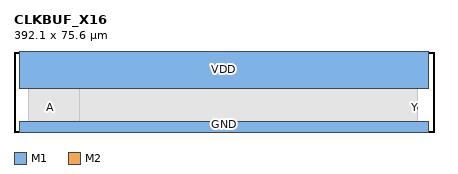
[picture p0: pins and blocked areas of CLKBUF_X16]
MACRO CLKBUF_X16
  CLASS CORE ;
  ORIGIN 0 0 ;
  SIZE 392.100 BY 75.600 ;
  SYMMETRY X Y ;
  SITE TR1um_access_site ;
  PIN VDD
    DIRECTION INOUT ;
    USE POWER ;
    PORT
      LAYER M1 ;
        RECT 5.000 41.000 387.100 75.600 ;
    END
  END VDD
  PIN GND
    DIRECTION INOUT ;
    USE GROUND ;
    PORT
      LAYER M1 ;
        RECT 5.000 0.000 387.100 9.800 ;
    END
  END GND
  PIN A
    DIRECTION INPUT ;
    USE SIGNAL ;
    PORT
      LAYER M2 ;
        RECT 32.100 21.600 35.500 25.000 ;
    END
  END A
  PIN Y
    DIRECTION OUTPUT ;
    USE SIGNAL ;
    PORT
      LAYER M2 ;
        RECT 373.100 21.600 376.500 25.000 ;
    END
  END Y
  OBS
    LAYER M1 ;
      RECT 17.100 16.400 51.700 34.400 ;
    LAYER M1 ;
      RECT 13.100 6.400 369.700 51.200 ;
    LAYER M1 ;
      RECT 61.100 6.400 376.500 51.200 ;
    LAYER V1 ;
      RECT 33.100 22.600 34.500 24.000 ;
    LAYER V1 ;
      RECT 374.100 22.600 375.500 24.000 ;
  END
END CLKBUF_X16
